VERSION 5.7 ;
  NOWIREEXTENSIONATPIN ON ;
  DIVIDERCHAR "/" ;
  BUSBITCHARS "[]" ;
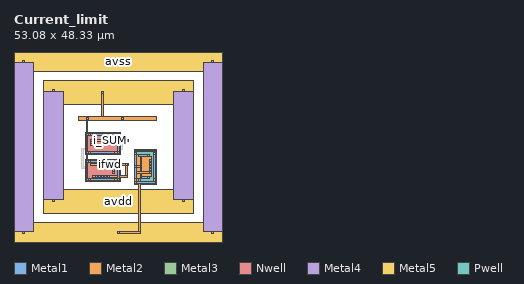
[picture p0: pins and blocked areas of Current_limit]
MACRO Current_limit
  CLASS BLOCK ;
  FOREIGN Current_limit ;
  ORIGIN 0.000 0.000 ;
  SIZE 53.080 BY 48.330 ;
  PIN i_SUM
    ANTENNADIFFAREA 0.300000 ;
    PORT
      LAYER Metal1 ;
        RECT 19.510 25.495 20.010 25.995 ;
        RECT 19.530 24.945 19.990 25.495 ;
        RECT 19.510 24.445 20.010 24.945 ;
      LAYER Metal2 ;
        RECT 19.510 25.495 29.235 25.995 ;
        RECT 19.510 24.445 20.010 24.945 ;
      LAYER Metal3 ;
        RECT 28.485 25.495 28.985 25.995 ;
    END
  END i_SUM
  PIN ifwd
    ANTENNAGATEAREA 2.500000 ;
    ANTENNADIFFAREA 0.300000 ;
    PORT
      LAYER Metal1 ;
        RECT 25.070 19.395 25.570 19.895 ;
        RECT 25.090 18.045 25.550 19.395 ;
        RECT 25.070 17.545 25.570 18.045 ;
        RECT 20.690 16.505 21.190 17.005 ;
        RECT 21.490 16.505 21.990 17.005 ;
        RECT 22.290 16.505 22.790 17.005 ;
        RECT 23.090 16.505 23.590 17.005 ;
        RECT 23.890 16.505 24.390 17.005 ;
      LAYER Metal2 ;
        RECT 19.510 19.395 29.235 19.895 ;
        RECT 25.070 17.545 25.570 18.045 ;
        RECT 28.485 17.005 28.985 19.395 ;
        RECT 20.040 16.505 28.985 17.005 ;
      LAYER Metal3 ;
        RECT 28.485 19.395 28.985 19.895 ;
    END
  END ifwd
  PIN avdd
    ANTENNADIFFAREA 18.172800 ;
    PORT
      LAYER Nwell ;
        RECT 18.110 22.300 26.970 27.900 ;
        RECT 18.110 15.400 26.970 21.000 ;
      LAYER Metal1 ;
        RECT 18.340 31.150 18.840 31.650 ;
        RECT 18.340 27.690 18.800 31.150 ;
        RECT 18.340 27.190 18.840 27.690 ;
        RECT 19.490 27.190 25.590 27.690 ;
        RECT 26.240 27.190 26.740 27.690 ;
        RECT 18.340 23.010 18.800 27.190 ;
        RECT 26.280 23.010 26.740 27.190 ;
        RECT 18.340 22.510 18.840 23.010 ;
        RECT 19.490 22.510 25.590 23.010 ;
        RECT 26.240 22.510 26.740 23.010 ;
        RECT 18.340 20.790 18.800 22.510 ;
        RECT 18.340 20.290 18.840 20.790 ;
        RECT 19.490 20.290 25.590 20.790 ;
        RECT 26.240 20.290 26.740 20.790 ;
        RECT 18.340 16.110 18.800 20.290 ;
        RECT 26.280 16.110 26.740 20.290 ;
        RECT 18.340 15.610 18.840 16.110 ;
        RECT 19.490 15.610 25.590 16.110 ;
        RECT 26.240 15.610 26.740 16.110 ;
      LAYER Metal2 ;
        RECT 22.290 31.900 22.790 38.285 ;
        RECT 16.340 30.900 36.280 31.900 ;
        RECT 18.340 27.190 26.740 27.690 ;
        RECT 18.340 22.510 26.740 23.010 ;
        RECT 18.340 20.290 26.740 20.790 ;
        RECT 18.340 15.610 26.740 16.110 ;
      LAYER Metal3 ;
        RECT 22.290 37.785 22.790 38.285 ;
        RECT 27.260 31.150 27.760 31.650 ;
      LAYER Metal4 ;
        RECT 9.790 38.350 10.290 38.850 ;
        RECT 42.870 38.350 43.370 38.850 ;
        RECT 7.540 10.845 12.540 38.350 ;
        RECT 22.290 37.785 22.790 38.285 ;
        RECT 40.620 10.845 45.620 38.350 ;
        RECT 9.790 10.350 10.290 10.845 ;
        RECT 42.870 10.350 43.370 10.845 ;
      LAYER Metal5 ;
        RECT 7.540 34.965 45.620 41.095 ;
        RECT 7.540 7.235 45.620 13.365 ;
    END
  END avdd
  PIN avss
    ANTENNAGATEAREA 2.500000 ;
    ANTENNADIFFAREA 9.686399 ;
    PORT
      LAYER Pwell ;
        RECT 30.550 14.745 36.150 23.605 ;
      LAYER Metal1 ;
        RECT 30.760 22.915 35.940 23.375 ;
        RECT 30.760 22.875 31.260 22.915 ;
        RECT 35.440 22.875 35.940 22.915 ;
        RECT 30.760 19.425 31.260 22.225 ;
        RECT 31.655 22.185 32.155 22.205 ;
        RECT 33.505 22.185 34.005 22.205 ;
        RECT 31.655 21.725 34.005 22.185 ;
        RECT 31.655 21.705 32.155 21.725 ;
        RECT 33.505 21.705 34.005 21.725 ;
        RECT 34.545 20.525 35.045 21.025 ;
        RECT 34.545 19.725 35.045 20.225 ;
        RECT 30.690 18.925 31.260 19.425 ;
        RECT 34.545 18.925 35.045 19.425 ;
        RECT 30.760 16.125 31.260 18.925 ;
        RECT 34.545 18.125 35.045 18.625 ;
        RECT 34.545 17.325 35.045 17.825 ;
        RECT 32.455 16.625 32.955 16.645 ;
        RECT 33.505 16.625 34.005 16.645 ;
        RECT 32.455 16.165 34.005 16.625 ;
        RECT 32.455 16.145 32.955 16.165 ;
        RECT 33.505 16.145 34.005 16.165 ;
        RECT 35.440 16.125 35.940 22.225 ;
        RECT 30.760 15.435 31.260 15.475 ;
        RECT 35.440 15.435 35.940 15.475 ;
        RECT 30.760 14.975 35.940 15.435 ;
      LAYER Metal2 ;
        RECT 30.760 22.205 31.260 23.375 ;
        RECT 30.760 19.425 32.155 22.205 ;
        RECT 30.690 18.925 32.155 19.425 ;
        RECT 30.760 17.825 32.155 18.925 ;
        RECT 32.455 21.675 34.545 22.205 ;
        RECT 32.455 17.825 35.045 21.675 ;
        RECT 30.760 17.325 35.045 17.825 ;
        RECT 30.760 16.145 32.155 17.325 ;
        RECT 32.455 16.675 35.045 17.325 ;
        RECT 32.455 16.145 34.545 16.675 ;
        RECT 30.760 14.975 31.260 16.145 ;
        RECT 31.655 2.750 32.155 16.145 ;
        RECT 35.440 14.975 35.940 23.375 ;
        RECT 26.290 2.250 32.155 2.750 ;
      LAYER Metal3 ;
        RECT 26.290 2.250 26.790 2.750 ;
      LAYER Metal4 ;
        RECT 2.250 45.580 2.750 46.080 ;
        RECT 50.330 45.580 50.830 46.080 ;
        RECT 0.000 2.750 5.000 45.580 ;
        RECT 48.080 2.750 53.080 45.580 ;
        RECT 2.250 2.250 2.750 2.750 ;
        RECT 26.290 2.250 26.790 2.750 ;
        RECT 50.330 2.250 50.830 2.750 ;
      LAYER Metal5 ;
        RECT 0.000 43.330 53.080 48.330 ;
        RECT 0.000 0.000 53.080 5.000 ;
    END
  END avss
  OBS
      LAYER Metal1 ;
        RECT 25.070 26.295 25.570 26.795 ;
        RECT 25.090 24.945 25.550 26.295 ;
        RECT 25.070 24.445 25.570 24.945 ;
        RECT 20.690 23.405 21.190 23.905 ;
        RECT 21.490 23.405 21.990 23.905 ;
        RECT 22.290 23.405 22.790 23.905 ;
        RECT 23.090 23.405 23.590 23.905 ;
        RECT 23.890 23.405 24.390 23.905 ;
        RECT 19.510 18.595 20.010 19.095 ;
        RECT 19.530 18.045 19.990 18.595 ;
        RECT 19.510 17.545 20.010 18.045 ;
      LAYER Metal2 ;
        RECT 19.510 26.295 27.570 26.795 ;
        RECT 25.070 24.445 25.570 24.945 ;
        RECT 17.210 23.405 27.570 23.905 ;
        RECT 17.210 18.595 25.570 19.095 ;
        RECT 19.510 17.545 20.010 18.045 ;
      LAYER Metal3 ;
        RECT 17.210 18.595 17.710 23.905 ;
        RECT 27.070 23.405 27.570 26.795 ;
  END
END Current_limit
END LIBRARY

